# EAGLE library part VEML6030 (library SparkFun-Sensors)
VEML6030 Ambient Light Sensor VEML6030 is a high accuracy ambient light digital 16-bit resolution sensor in a miniature transparent 2 mm x 2 mm package. It includes a high sensitive photodiode, a low noise amplifier, a 16-bit A/D converter and supports an easy to use I2C bus communication interface and additional interrupt feature.

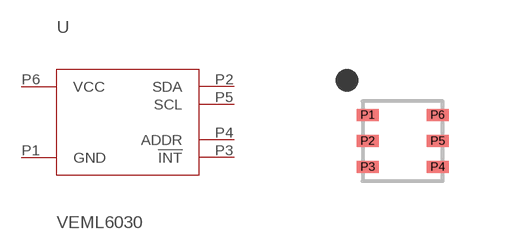
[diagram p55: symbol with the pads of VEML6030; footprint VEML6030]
Designator prefix U

## VEML6030 (PROD_ID: SEN-14447)  [VEML6030]
P1  GND  pwr
P2  SDA
P3  !INT  out
P4  ADDR
P5  SCL
P6  VCC  pwr

## Footprint VEML6030 (pad centres in mm)
VEML6030 Ambient Light Sensor Physical Characteristics 6 Pin SMD Package 2mm x 2mm x .83mm .65mm Pitch .45mm x .4mm Pad Size
smd 0.55 x 0.3: P1 -0.88,0.65; P2 -0.88,0; P3 -0.88,-0.65; P4 0.87,-0.65; P5 0.87,0; P6 0.87,0.65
